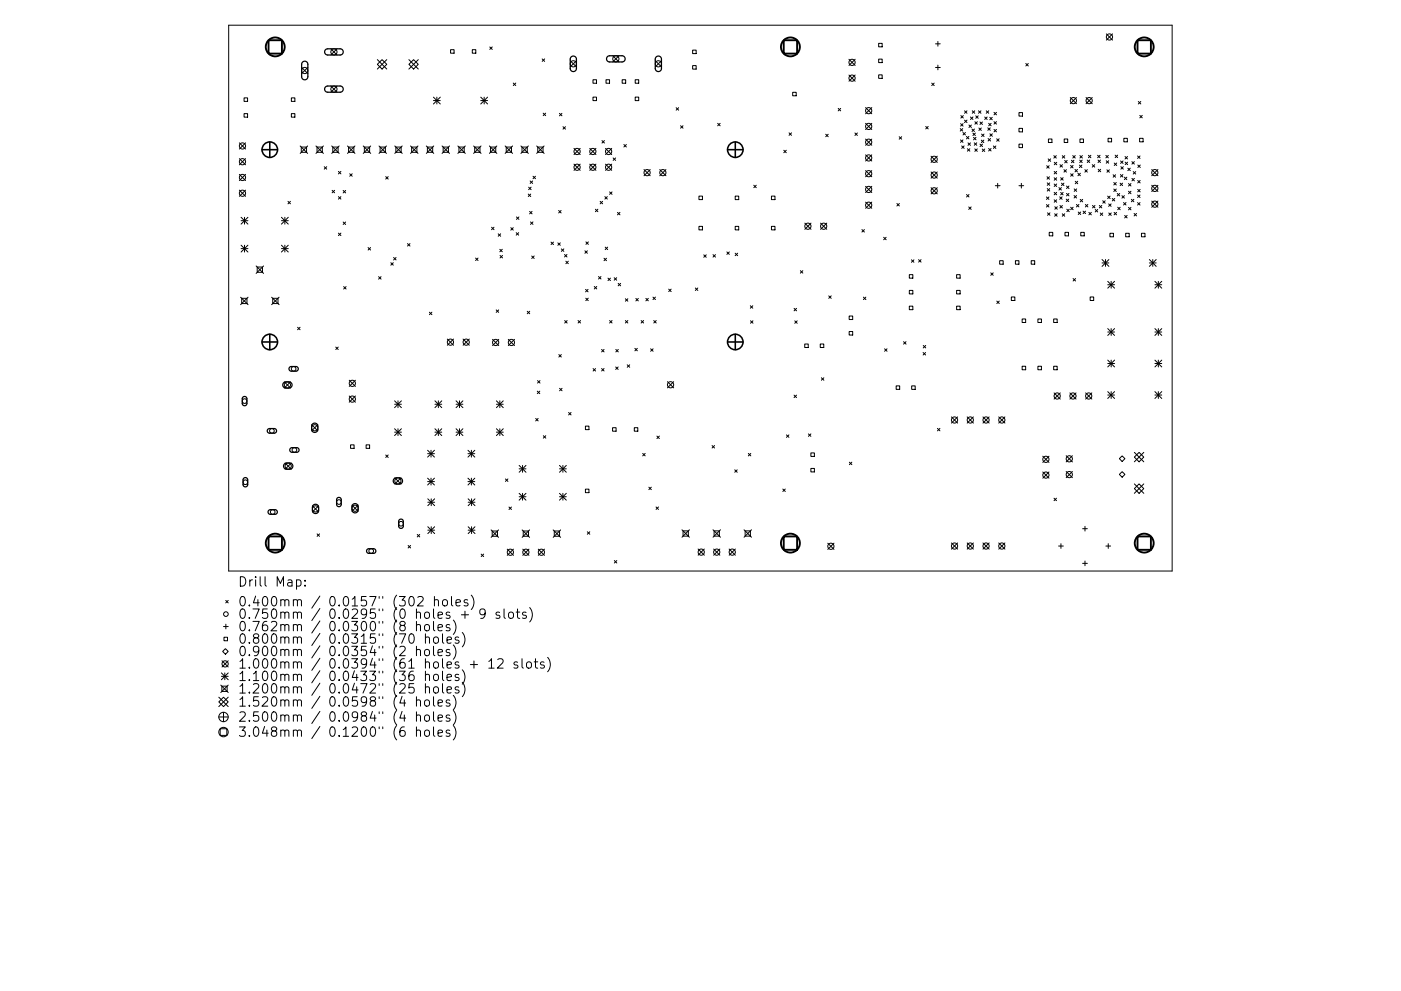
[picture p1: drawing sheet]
<svg xmlns="http://www.w3.org/2000/svg" width="297mm" height="210mm" viewBox="0 0 297 210" stroke-linecap="round" stroke-linejoin="round" font-family="sans-serif">
<defs><g id="words">
<g font-size="2.8">
<text x="50.4" y="125.1">Drill</text>
<text x="58.4" y="125.1">Map:</text>
<text x="50.4" y="129.3">0.400mm</text>
<text x="50.4" y="131.9">0.750mm</text>
<text x="69.8" y="129.3">0.0157&quot;</text>
<text x="69.8" y="131.9">0.0295&quot;</text>
<text x="83.6" y="129.3">(302</text>
<text x="83.6" y="131.9">(0</text>
<text x="88.5" y="131.9">holes</text>
<text x="92.3" y="129.3">holes)</text>
<text x="98.2" y="131.9">+</text>
<text x="102.4" y="131.9">9</text>
<text x="106.1" y="131.9">slots)</text>
<text x="50.4" y="134.5">0.762mm</text>
<text x="50.4" y="137.2">0.800mm</text>
<text x="69.8" y="134.5">0.0300&quot;</text>
<text x="69.8" y="137.2">0.0315&quot;</text>
<text x="83.6" y="134.5">(8</text>
<text x="83.6" y="137.2">(70</text>
<text x="88.5" y="134.5">holes)</text>
<text x="90.4" y="137.2">holes)</text>
<text x="50.4" y="139.8">0.900mm</text>
<text x="50.4" y="142.5">1.000mm</text>
<text x="69.8" y="139.8">0.0354&quot;</text>
<text x="69.8" y="142.5">0.0394&quot;</text>
<text x="83.6" y="139.8">(2</text>
<text x="83.6" y="142.5">(61</text>
<text x="88.5" y="139.8">holes)</text>
<text x="90.4" y="142.5">holes</text>
<text x="100.1" y="142.5">+</text>
<text x="109.9" y="142.5">slots)</text>
<text x="50.4" y="145.1">1.100mm</text>
<text x="50.4" y="147.8">1.200mm</text>
<text x="69.8" y="145.1">0.0433&quot;</text>
<text x="69.8" y="147.8">0.0472&quot;</text>
<text x="83.6" y="145.1">(36</text>
<text x="83.6" y="147.8">(25</text>
<text x="90.4" y="145.1">holes)</text>
<text x="90.4" y="147.8">holes)</text>
<text x="50.4" y="150.5">1.520mm</text>
<text x="50.4" y="153.7">2.500mm</text>
<text x="69.8" y="150.5">0.0598&quot;</text>
<text x="69.8" y="153.7">0.0984&quot;</text>
<text x="83.6" y="150.5">(4</text>
<text x="83.6" y="153.7">(4</text>
<text x="88.5" y="150.5">holes)</text>
<text x="88.5" y="153.7">holes)</text>
<text x="50.4" y="156.9">3.048mm</text>
<text x="69.8" y="156.9">0.1200&quot;</text>
<text x="83.6" y="156.9">(6</text>
<text x="88.5" y="156.9">holes)</text>
</g>
</g></defs>
<g fill="none" stroke="#000" stroke-width=".21">
<path d="M48.5 5.3h200v115.9h-200zM64 14.3l1.3 1.3M65.3 14.3l-1.3 1.3M70.1 10.4l1.4 1.3M70.1 18.3l1.4 1.3M71.5 10.4l-1.4 1.3M71.5 18.3l-1.4 1.3M80 12.7l2 2M81 12.7l1 1-1 1-1-1zM82 12.7l-2 2M86.7 12.7l2 2M87.7 12.7l1 1-1 1-1-1z"/>
<path d="M88.7 12.7l-2 2M95.5 10.5h.8v.8h-.8zM100.1 10.5h.8v.8h-.8zM103.8 10l.6 .5M104.4 10l-.6 .5M108.8 17.6l.6 .6M109.4 17.6l-.6 .6M114.9 12.5l.6 .5M115.5 12.5l-.6 .5M120.9 12.9l1.3 1.3M122.2 12.9l-1.3 1.3M125.7 16.9h.8v.8h-.8z"/>
<path d="M128.5 16.9h.7v.8h-.7zM129.9 11.8l1.3 1.3M131.2 11.8l-1.3 1.3M131.9 16.9h.8v.8h-.8zM134.7 16.9h.7v.8h-.7zM138.9 12.9l1.3 1.3M140.2 12.9l-1.3 1.3M146.9 10.6h.7v.8h-.7zM146.9 13.9h.7v.8h-.7zM168.1 19.6h.7v.7h-.7zM180 12.6l1.3 1.3M180 15.9l1.3 1.3"/>
<path d="M181.3 12.6l-1.3 1.3M181.3 15.9l-1.3 1.3M186.3 9.2h.7v.7h-.7zM186.3 12.5h.7v.8h-.7zM186.3 15.9h.7v.7h-.7zM197.5 17.6l.6 .6M198.1 17.6l-.6 .6M198.3 9.3h1.1M198.3 14.3h1.1M198.9 8.8v1M198.9 13.8v1M217.5 13.5l.5 .5"/>
<path d="M218 13.5l-.5 .5M234.6 7.2l1.3 1.3M235.9 7.2l-1.3 1.3M50.7 30.3l1.4 1.3M50.7 33.7l1.4 1.3M50.7 37l1.4 1.3M51.7 20.8h.8v.7h-.8zM51.7 24.1h.8v.8h-.8zM52.1 30.3l-1.4 1.3M52.1 33.7l-1.4 1.3M52.1 37l-1.4 1.3M61.8 20.8h.7v.7h-.7z"/>
<path d="M61.8 24.1h.7v.8h-.7zM63.6 31l1.6 1.5M63.9 31.2h1.1v1.1h-1.1zM65.2 31l-1.6 1.5M67 31l1.6 1.5M67.2 31.2h1.1v1.1h-1.1zM68.6 31l-1.6 1.5M68.7 35.4l.6 .5M69.3 35.4l-.6 .5M70.3 31l1.6 1.5M70.6 31.2h1.1v1.1h-1.1zM71.8 36.4l.5 .5"/>
<path d="M71.9 31l-1.6 1.5M72.3 36.4l-.5 .5M73.7 31l1.6 1.5M73.9 31.2h1.1v1.1h-1.1zM74.1 36.9l.6 .5M74.7 36.9l-.6 .5M75.3 31l-1.6 1.5M77 31l1.6 1.5M77.2 31.2h1.2v1.1h-1.2zM78.6 31l-1.6 1.5M80.4 31l1.5 1.5M80.6 31.2h1.1v1.1h-1.1z"/>
<path d="M81.8 37.5l.5 .5M81.9 31l-1.5 1.5M82.3 37.5l-.5 .5M83.7 31l1.6 1.5M83.9 31.2h1.1v1.1h-1.1zM85.3 31l-1.6 1.5M87 31l1.6 1.5M87.3 31.2h1.1v1.1h-1.1zM88.6 31l-1.6 1.5M90.4 31l1.6 1.5M90.6 31.2h1.1v1.1h-1.1zM91.9 20.6l1.4 1.5"/>
<path d="M91.9 21.3h1.4M92 31l-1.6 1.5M92.6 20.6v1.5M93.3 20.6l-1.4 1.5M93.7 31l1.6 1.5M94 31.2h1.1v1.1h-1.1zM95.3 31l-1.6 1.5M97.1 31l1.6 1.5M97.3 31.2h1.1v1.1h-1.1zM98.7 31l-1.6 1.5M100.4 31l1.6 1.5M100.6 31.2h1.2v1.1h-1.2z"/>
<path d="M101.9 21.3h1.5M101.9 20.6l1.5 1.5M102 31l-1.6 1.5M102.7 20.6v1.5M103.4 20.6l-1.5 1.5M103.8 31l1.5 1.5M104 31.2h1.1v1.1h-1.1zM105.3 31l-1.5 1.5M107.1 31l1.6 1.5M107.3 31.2h1.1v1.1h-1.1zM108.7 31l-1.6 1.5M110.4 31l1.6 1.5"/>
<path d="M110.7 31.2h1.1v1.1h-1.1zM112 31l-1.6 1.5M112.1 39.7l.5 .5M112.4 38.4l.5 .5M112.6 39.7l-.5 .5M112.9 38.4l-.5 .5M113 37.4l.5 .5M113.5 37.4l-.5 .5M113.8 31l1.6 1.5M114 31.2h1.1v1.1h-1.1zM115.2 24l.5 .5M115.4 31l-1.6 1.5"/>
<path d="M115.7 24l-.5 .5M118.6 24l.5 .6M119.1 24l-.5 .6M119.4 26.9l.5 .5M119.9 26.9l-.5 .5M121.7 31.5l1.3 1.3M121.7 34.8l1.3 1.3M123 31.5l-1.3 1.3M123 34.8l-1.3 1.3M125 31.5l1.4 1.3M125 34.8l1.4 1.3M125.7 20.6h.8v.7h-.8z"/>
<path d="M126.4 31.5l-1.4 1.3M126.4 34.8l-1.4 1.3M127.6 29.8l.6 .6M128.2 29.8l-.6 .6M128.4 34.8l1.3 1.3M128.4 31.5l1.3 1.3M129.7 31.5l-1.3 1.3M129.7 34.8l-1.3 1.3M130 33.5l.5 .5M130.5 33.5l-.5 .5M132.3 30.7l.5 .5M132.8 30.7l-.5 .5"/>
<path d="M134.7 20.6h.7v.7h-.7zM136.5 36l1.4 1.3M137.9 36l-1.4 1.3M139.9 36l1.3 1.3M141.2 36l-1.3 1.3M143.4 22.8l.5 .6M143.9 22.8l-.5 .6M144.3 26.7l.5 .5M144.8 26.7l-.5 .5M152.2 26.2l.5 .5M152.7 26.2l-.5 .5M159.8 39.3l.5 .5"/>
<path d="M160.3 39.3l-.5 .5M166.2 31.9l.5 .5M166.7 31.9l-.5 .5M167.3 28.2l.5 .5M167.8 28.2l-.5 .5M175.1 28.5l.5 .5M175.6 28.5l-.5 .5M177.7 23l.5 .5M178.2 23l-.5 .5M181.3 28.2l.5 .5M181.8 28.2l-.5 .5M183.5 22.8l1.3 1.3"/>
<path d="M183.5 26.2l1.3 1.3M183.5 29.5l1.3 1.3M183.5 32.9l1.3 1.3M183.5 36.2l1.3 1.3M183.5 39.5l1.3 1.4M184.8 22.8l-1.3 1.3M184.8 26.2l-1.3 1.3M184.8 29.5l-1.3 1.3M184.8 32.9l-1.3 1.3M184.8 36.2l-1.3 1.3M184.8 39.5l-1.3 1.4M190.6 29l.6 .5"/>
<path d="M191.2 29l-.6 .5M196.3 26.8l.5 .6M196.8 26.8l-.5 .6M197.4 33.1l1.3 1.4M197.4 36.5l1.3 1.3M197.4 39.8l1.3 1.3M198.7 36.5l-1.3 1.3M198.7 33.1l-1.3 1.4M198.7 39.8l-1.3 1.3M203.6 27.3l.5 .5M203.6 29.7l.6 .5M203.7 26.2l.5 .6"/>
<path d="M203.7 24.5l.5 .5M203.9 31l.5 .5M204.1 27.3l-.5 .5M204.2 28.1l.5 .5M204.2 29.7l-.6 .5M204.2 26.2l-.5 .6M204.2 24.5l-.5 .5M204.4 31l-.5 .5M204.5 23.5l.5 .5M204.5 25.5l.5 .5M204.7 28.1l-.5 .5M204.9 28.9l.5 .6"/>
<path d="M205 23.5l-.5 .5M205 25.5l-.5 .5M205.1 31.5l.5 .6M205.2 30.3l.6 .5M205.4 28.9l-.5 .6M205.4 26.5l.6 .5M205.6 31.5l-.5 .6M205.8 30.3l-.6 .5M205.8 24.8l.5 .6M206 26.5l-.6 .5M206.1 27.4l.5 .5M206.1 23.5l.6 .5"/>
<path d="M206.3 28.2l.5 .6M206.3 24.8l-.5 .6M206.4 29.1l.5 .6M206.6 30.3l.5 .5M206.6 27.4l-.5 .5M206.7 23.5l-.6 .5M206.7 31.6l.5 .5M206.7 25.8l.5 .6M206.8 28.2l-.5 .6M206.9 24.6l.5 .5M206.9 29.1l-.5 .6M207.1 30.3l-.5 .5"/>
<path d="M207.2 31.6l-.5 .5M207.2 25.8l-.5 .6M207.4 24.6l-.5 .5M207.5 23.5l.5 .5M207.5 27.2l.6 .5M207.8 25.9l.5 .5M207.8 30.6l.5 .5M208 23.5l-.5 .5M208.1 27.2l-.6 .5M208.1 29.7l.5 .6M208.1 28.4l.5 .6M208.3 31.6l.5 .5"/>
<path d="M208.3 25.9l-.5 .5M208.3 30.6l-.5 .5M208.6 29.7l-.5 .6M208.6 28.4l-.5 .6M208.8 24.8l.5 .6M208.8 31.6l-.5 .5M209.1 23.5l.5 .5M209.3 24.8l-.5 .6M209.4 27.1l.6 .6M209.5 29.4l.5 .5M209.6 31.5l.5 .5M209.6 26.2l.5 .5"/>
<path d="M209.6 23.5l-.5 .5M209.9 24.9l.5 .5M209.9 28.4l.5 .5M210 27.1l-.6 .6M210 29.4l-.5 .5M210.1 31.5l-.5 .5M210.1 26.2l-.5 .5M210.4 24.9l-.5 .5M210.4 28.4l-.5 .5M210.6 31l.5 .5M210.7 25.8l.6 .5M210.7 23.8l.6 .6"/>
<path d="M210.7 27.5l.6 .5M211 39.4h1M211.1 31l-.5 .5M211.3 25.8l-.6 .5M211.3 23.8l-.6 .6M211.3 27.5l-.6 .5M211.3 29.4l.5 .6M211.5 38.9v1M211.8 29.4l-.5 .6M216 39.4h1M216 23.9h.8v.7h-.8zM216 27.2h.8v.8h-.8z"/>
<path d="M216 30.6h.8v.7h-.8zM216.5 38.9v1M221.9 35.2l.5 .5M222 37.5l.5 .5M222 38.8l.6 .5M222.2 33.7l.6 .5M222.3 29.5h.7v.7h-.7zM222.4 35.2l-.5 .5M222.5 37.5l-.5 .5M222.6 38.8l-.6 .5M222.8 33.7l-.6 .5M223.4 33l.6 .5"/>
<path d="M223.5 39l.5 .6M223.5 36.4l.5 .5M223.5 37.7l.5 .5M223.5 34.4l.6 .6M224 33l-.6 .5M224 36.4l-.5 .5M224 37.7l-.5 .5M224 39l-.5 .6M224.1 34.4l-.6 .6M224.5 39.8l.5 .5M224.7 34.9l.6 .6M224.9 37.7l.5 .5"/>
<path d="M225 39.8l-.5 .5M225.1 38.9l.5 .5M225.2 33l.5 .5M225.3 34.9l-.6 .6M225.4 37.7l-.5 .5M225.6 38.9l-.5 .5M225.6 36l.5 .5M225.6 29.5h.8v.7h-.8zM225.7 34l.6 .6M225.7 33l-.5 .5M226.1 36l-.5 .5M226.1 39.5l.5 .5"/>
<path d="M226.3 34l-.6 .6M226.6 39.5l-.5 .5M226.9 20.7l1.3 1.3M227 35.1l.5 .5M227 36.9l.5 .5M227.2 34l.5 .5M227.4 33l.6 .5M227.5 35.1l-.5 .5M227.5 36.9l-.5 .5M227.7 34l-.5 .5M227.9 36l.5 .5M228 33l-.6 .5"/>
<path d="M228 38.5l.5 .5M228.2 20.7l-1.3 1.3M228.4 36l-.5 .5M228.5 38.5l-.5 .5M228.5 36.8l.6 .5M228.9 35l.5 .6M228.9 34l.5 .5M229 33l.5 .5M229 29.5h.7v.7h-.7zM229.1 36.8l-.6 .5M229.4 35l-.5 .6M229.4 34l-.5 .5"/>
<path d="M229.5 33l-.5 .5M230 36l.5 .5M230.3 20.7l1.3 1.3M230.5 34l.5 .5M230.5 36l-.5 .5M230.8 32.9l.5 .6M231 34l-.5 .5M231.3 32.9l-.5 .6M231.6 34.9l.5 .6M231.6 20.7l-1.3 1.3M232.1 34.9l-.5 .6M232.7 32.9l.5 .6"/>
<path d="M232.8 34l.5 .5M232.8 35.9l.6 .5M233.2 32.9l-.5 .6M233.3 34l-.5 .5M233.4 35.9l-.6 .5M234.5 33l.5 .5M234.5 34.1l.6 .5M234.7 36l.5 .5M234.9 29.3h.8v.8h-.8zM235 33l-.5 .5M235.1 34.1l-.6 .5M235.2 36l-.5 .5"/>
<path d="M236 37.1l.5 .5M236.1 38.7l.6 .5M236.2 34.6l.6 .5M236.4 32.9l.6 .5M236.5 37.1l-.5 .5M236.7 38.7l-.6 .5M236.8 34.6l-.6 .5M237 32.9l-.6 .5M237.5 38.9l.5 .5M237.5 37l.6 .6M237.6 34.1l.5 .6M237.6 35.4l.6 .5"/>
<path d="M238 38.9l-.5 .5M238.1 37l-.6 .6M238.1 34.1l-.5 .6M238.2 35.4l-.6 .5M238.3 29.3h.7v.8h-.7zM238.4 37.6l.5 .5M238.5 33.2l.6 .5M238.6 34.4l.5 .5M238.9 37.6l-.5 .5M239.1 33.2l-.6 .5M239.1 34.4l-.5 .5M239.1 35.7l.5 .5"/>
<path d="M239.3 38.9l.5 .6M239.6 35.7l-.5 .5M239.8 38.9l-.5 .6M240 34.3l.5 .5M240 37.9l.5 .5M240.3 36.4l.5 .5M240.5 34.3l-.5 .5M240.5 37.9l-.5 .5M240.8 36.4l-.5 .5M241.2 33.1l.5 .5M241.2 38.3l.5 .5M241.2 35l.6 .5"/>
<path d="M241.3 21.5l.6 .6M241.6 29.3h.8v.8h-.8zM241.7 24.5l.5 .5M241.7 33.1l-.5 .5M241.7 38.3l-.5 .5M241.8 35l-.6 .5M241.9 21.5l-.6 .6M242.2 24.5l-.5 .5M244.2 36l1.3 1.3M244.2 39.3l1.3 1.3M245.5 36l-1.3 1.3M245.5 39.3l-1.3 1.3"/>
<path d="M50.7 40.3l1.4 1.4M51.1 46.1l1.5 1.5M51.1 46.8h1.5M51.1 52l1.5 1.5M51.1 52.7h1.5M51.8 46.1v1.5M51.8 52v1.5M52.1 40.3l-1.4 1.4M52.6 46.1l-1.5 1.5M52.6 52l-1.5 1.5M54.3 56.4l1.6 1.6M54.5 56.7h1.2v1.1h-1.2z"/>
<path d="M55.9 56.4l-1.6 1.6M59.7 46.8h1.4M59.7 52.7h1.4M59.7 46.1l1.4 1.5M59.7 52l1.4 1.5M60.4 46.1v1.5M60.4 52v1.5M61.1 42.7l.5 .5M61.1 46.1l-1.4 1.5M61.1 52l-1.4 1.5M61.6 42.7l-.5 .5M70.4 40.4l.5 .5"/>
<path d="M70.9 40.4l-.5 .5M71.8 41.7l.5 .5M71.8 49.5l.5 .5M72.3 41.7l-.5 .5M72.3 49.5l-.5 .5M72.8 40.4l.5 .5M72.8 47.1l.5 .5M73.3 40.4l-.5 .5M73.3 47.1l-.5 .5M78 52.5l.6 .6M78.6 52.5l-.6 .6M80.3 58.7l.5 .5"/>
<path d="M80.8 58.7l-.5 .5M82.9 55.7l.5 .6M83.4 55.7l-.5 .6M83.5 54.6l.5 .6M84 54.6l-.5 .6M86.4 51.7l.5 .5M86.9 51.7l-.5 .5M100.8 54.8l.6 .5M101.4 54.8l-.6 .5M104.2 48.2l.5 .5M104.7 48.2l-.5 .5M105.6 49.6l.6 .5"/>
<path d="M106 52.9l.5 .5M106 54.2l.5 .5M106.2 49.6l-.6 .5M106.5 52.9l-.5 .5M106.5 54.2l-.5 .5M108.3 48.3l.5 .5M108.8 48.3l-.5 .5M109.4 49.4l.6 .5M109.5 46l.5 .6M110 49.4l-.6 .5M110 46l-.5 .6M112 41.2l.5 .5"/>
<path d="M112.3 44.9l.5 .5M112.5 47.1l.5 .5M112.5 41.2l-.5 .5M112.7 54.3l.6 .5M112.8 44.9l-.5 .5M113 47.1l-.5 .5M113.3 54.3l-.6 .5M116.8 51.4l.6 .5M117.4 51.4l-.6 .5M118.3 51.5l.5 .5M118.4 44.7l.6 .5M118.8 51.5l-.5 .5"/>
<path d="M119 44.7l-.6 .5M119 52.8l.5 .5M119.5 52.8l-.5 .5M119.7 54l.5 .5M120 55.4l.5 .5M120.2 54l-.5 .5M120.5 55.4l-.5 .5M124 53.2l.5 .5M124.2 51.3l.6 .5M124.5 53.2l-.5 .5M124.8 51.3l-.6 .5M126.2 44.4l.6 .5"/>
<path d="M126.8 44.4l-.6 .5M126.9 58.7l.5 .5M127.2 42.7l.6 .5M127.4 58.7l-.5 .5M127.8 42.7l-.6 .5M128.1 54.8l.5 .5M128.2 41.7l.6 .5M128.3 52.4l.5 .6M128.6 54.8l-.5 .5M128.8 41.7l-.6 .5M128.8 52.4l-.5 .6M128.9 59l.5 .5"/>
<path d="M129.2 40.7l.6 .5M129.4 59l-.5 .5M129.8 40.7l-.6 .5M130.2 58.9l.5 .5M130.7 58.9l-.5 .5M130.9 45.1l.5 .5M131.4 45.1l-.5 .5M148.2 41.6h.7v.8h-.7zM148.2 48h.7v.8h-.7zM149.2 54.1l.5 .5M149.7 54.1l-.5 .5M151.2 54l.5 .6"/>
<path d="M151.7 54l-.5 .6M154.1 53.4l.5 .6M154.6 53.4l-.5 .6M155.9 53.7l.5 .5M155.9 41.6h.7v.8h-.7zM155.9 48h.7v.8h-.7zM156.4 53.7l-.5 .5M163.6 41.6h.7v.8h-.7zM163.6 48h.7v.8h-.7zM169.7 57.4l.5 .6M170.2 57.4l-.5 .6M170.6 47.3l1.3 1.4"/>
<path d="M171.9 47.3l-1.3 1.4M174 47.3l1.3 1.4M175.3 47.3l-1.3 1.4M182.7 48.7l.6 .5M183.3 48.7l-.6 .5M183.5 42.9l1.3 1.3M184.8 42.9l-1.3 1.3M187.4 50.3l.5 .6M187.9 50.3l-.5 .6M190.2 43.2l.5 .5M190.7 43.2l-.5 .5M192.8 58.3h.7v.7h-.7z"/>
<path d="M193.2 55.1l.6 .6M193.8 55.1l-.6 .6M194.8 55.1l.5 .5M195.3 55.1l-.5 .5M202.8 58.3h.8v.7h-.8zM204.9 41.3l.6 .5M205.4 43.9l.5 .5M205.5 41.3l-.6 .5M205.9 43.9l-.5 .5M210.1 57.9l.5 .5M210.6 57.9l-.5 .5M211.9 55.3h.8v.8h-.8z"/>
<path d="M215.3 55.3h.7v.8h-.7zM218.6 55.3h.8v.8h-.8zM221.9 41.8l.5 .5M221.9 43.4l.5 .5M222 40l.6 .5M222.1 45.2l.5 .5M222.4 41.8l-.5 .5M222.4 43.4l-.5 .5M222.5 49.3h.7v.7h-.7zM222.6 40l-.6 .5M222.6 45.2l-.5 .5M223.5 40.8l.5 .5"/>
<path d="M223.5 42.4l.5 .5M223.6 45.4l.5 .5M223.6 43.9l.6 .5M224 40.8l-.5 .5M224 42.4l-.5 .5M224.1 45.4l-.5 .5M224.2 43.9l-.6 .5M224.7 41.8l.5 .5M224.7 43.6l.6 .5M224.9 40.8l.5 .6M225.2 41.8l-.5 .5M225.2 45.4l.5 .5"/>
<path d="M225.3 43.6l-.6 .5M225.4 40.8l-.5 .6M225.7 45.4l-.5 .5M225.8 49.3h.7v.7h-.7zM226.1 42.2l.5 .6M226.1 41l.5 .6M226.2 44.4l.5 .5M226.6 42.2l-.5 .6M226.6 41l-.5 .6M226.7 44.4l-.5 .5M227 44l.5 .5M227.5 59.1l.5 .5"/>
<path d="M227.5 44l-.5 .5M227.7 41.5l.5 .5M227.7 40.1l.6 .5M228 59.1l-.5 .5M228.2 43.4l.6 .5M228.2 41.5l-.5 .5M228.3 40.1l-.6 .5M228.6 45l.5 .5M228.8 43.4l-.6 .5M229 42.3l.6 .5M229.1 45l-.5 .5M229.1 49.3h.8v.7h-.8z"/>
<path d="M229.6 42.3l-.6 .5M229.6 44.8l.6 .5M230.1 43.4l.5 .5M230.2 44.8l-.6 .5M230.6 43.4l-.5 .5M230.9 45.1l.5 .5M231.4 45.1l-.5 .5M231.6 43.6l.6 .5M232.2 43.6l-.6 .5M232.2 44.4l.5 .6M232.7 44.4l-.5 .6M233.1 43.6l.5 .5"/>
<path d="M233.3 45.2l.5 .5M233.6 43.6l-.5 .5M233.7 55.1l1.4 1.4M233.7 55.8h1.4M233.8 45.2l-.5 .5M233.8 42.6l.5 .5M234.3 42.6l-.5 .5M234.4 55.1v1.4M234.8 41.6l.6 .5M234.9 59.7l1.4 1.4M235.1 43.3l.5 .5M235.1 45.2l.5 .5"/>
<path d="M235.1 55.1l-1.4 1.4M235.3 49.5h.8v.7h-.8zM235.4 41.6l-.6 .5M235.6 43.3l-.5 .5M235.6 59.7v1.4M235.6 45.2l-.5 .5M235.8 42.1l.5 .5M236.1 40.1l.6 .5M236.2 45.1l.5 .5M236.3 59.7l-1.4 1.4M236.3 42.1l-.5 .5M236.7 40.1l-.6 .5"/>
<path d="M236.7 45.1l-.5 .5M236.9 41l.5 .6M237 44l.5 .5M237.4 41l-.5 .6M237.5 44l-.5 .5M237.9 41.5l.5 .5M238.2 43l.5 .5M238.4 41.5l-.5 .5M238.4 45.7l.6 .5M238.7 49.5h.7v.7h-.7zM238.7 43l-.5 .5M239 45.7l-.6 .5"/>
<path d="M239.3 40.6l.5 .5M239.3 44l.5 .5M239.8 40.6l-.5 .5M239.8 44l-.5 .5M239.9 42.3l.5 .5M240.4 42.3l-.5 .5M240.4 45.3l.6 .5M241 45.3l-.6 .5M241.2 41.4l.5 .5M241.2 43l.5 .5M241.2 40.2l.5 .5M241.7 43l-.5 .5"/>
<path d="M241.7 41.4l-.5 .5M241.7 40.2l-.5 .5M242 49.5h.8v.7h-.8zM243.7 55.8h1.4M243.7 55.1l1.4 1.4M244.2 42.7l1.3 1.3M244.4 55.1v1.4M244.9 59.7l1.4 1.4M245.1 55.1l-1.4 1.4M245.5 42.7l-1.3 1.3M245.6 59.7v1.4M246.3 59.7l-1.4 1.4"/>
<path d="M51 63.1l1.6 1.5M51.2 63.3h1.2v1.1h-1.2zM52.6 63.1l-1.6 1.5M57.6 63.1l1.6 1.5M57.8 63.3h1.1v1.1h-1.1zM59.2 63.1l-1.6 1.5M63.1 69.4l.5 .6M63.6 69.4l-.5 .6M71.2 73.6l.5 .6M71.7 73.6l-.5 .6M72.9 60.8l.5 .5M73.4 60.8l-.5 .5"/>
<path d="M91 66.2l.6 .6M91.6 66.2l-.6 .6M94.8 71.9l1.4 1.4M96.2 71.9l-1.4 1.4M98.2 71.9l1.3 1.4M99.5 71.9l-1.3 1.4M104.4 72l1.3 1.3M105.2 65.8l.5 .5M105.7 65.8l-.5 .5M105.7 72l-1.3 1.3M107.8 72l1.3 1.3M109.1 72l-1.3 1.3"/>
<path d="M111.8 66l.5 .6M112.3 66l-.5 .6M118.5 75.2l.5 .6M119 75.2l-.5 .6M119.7 68l.5 .5M120.2 68l-.5 .5M122.6 68l.5 .5M123.1 68l-.5 .5M124.2 61.4l.5 .5M124.2 63.3l.5 .5M124.7 61.4l-.5 .5M124.7 63.3l-.5 .5"/>
<path d="M125.7 78.2l.6 .5M126 60.8l.5 .5M126.3 78.2l-.6 .5M126.5 60.8l-.5 .5M127.6 74.1l.5 .6M127.6 78.2l.5 .5M128.1 74.1l-.5 .6M128.1 78.2l-.5 .5M129.2 68l.6 .5M129.8 68l-.6 .5M130.5 77.9l.6 .5M130.6 74.1l.5 .6"/>
<path d="M131.1 77.9l-.6 .5M131.1 60.1l.5 .5M131.1 74.1l-.5 .6M131.6 60.1l-.5 .5M132.6 68l.5 .5M132.6 63.4l.5 .5M133 77.4l.5 .5M133.1 68l-.5 .5M133.1 63.4l-.5 .5M133.5 77.4l-.5 .5M134.6 73.9l.5 .5M134.8 63.3l.5 .5"/>
<path d="M135.1 73.9l-.5 .5M135.3 63.3l-.5 .5M135.9 68l.6 .5M136.5 68l-.6 .5M136.9 63.3l.6 .5M137.5 63.3l-.6 .5M137.9 74l.6 .5M138.4 63l.6 .6M138.5 74l-.6 .5M138.6 68l.5 .5M139 63l-.6 .6M139.1 68l-.5 .5"/>
<path d="M141.8 61.3l.5 .6M142.3 61.3l-.5 .6M147.4 61.1l.6 .5M148 61.1l-.6 .5M159.1 64.9l.5 .5M159.1 68.1l.5 .5M159.6 64.9l-.5 .5M159.6 68.1l-.5 .5M168.4 65.4l.5 .5M168.5 68.1l.5 .5M168.9 65.4l-.5 .5M169 68.1l-.5 .5"/>
<path d="M170.6 73h.8v.7h-.8zM173.9 73h.8v.7h-.8zM175.7 62.8l.5 .5M176.2 62.8l-.5 .5M180 67.1h.8v.7h-.8zM180 70.3h.8v.8h-.8zM183.1 63l.5 .6M183.6 63l-.5 .6M187.5 74l.6 .5M188.1 74l-.6 .5M191.6 72.5l.5 .5M192.1 72.5l-.5 .5"/>
<path d="M192.8 61.6h.7v.8h-.7zM192.8 65h.7v.7h-.7zM195.7 74.8l.5 .5M195.7 73.3l.6 .5M196.2 74.8l-.5 .5M196.3 73.3l-.6 .5M202.8 61.6h.8v.8h-.8zM202.8 65h.8v.7h-.8zM211.3 63.9l.6 .5M211.9 63.9l-.6 .5M214.4 63h.8v.8h-.8zM216.7 67.7h.8v.7h-.8z"/>
<path d="M216.7 77.7h.8v.8h-.8zM220.1 67.7h.7v.7h-.7zM220.1 77.7h.7v.8h-.7zM223.4 67.7h.7v.7h-.7zM223.4 77.7h.7v.8h-.7zM231.1 63h.8v.8h-.8zM234.9 60.4h1.4M234.9 69.7l1.4 1.5M234.9 70.4h1.4M234.9 76.4l1.4 1.5M234.9 77.1h1.4M235.6 69.7v1.5"/>
<path d="M235.6 76.4v1.5M236.3 69.7l-1.4 1.5M236.3 76.4l-1.4 1.5M244.9 69.7l1.4 1.5M244.9 76.4l1.4 1.5M244.9 60.4h1.4M244.9 70.4h1.4M244.9 77.1h1.4M245.6 69.7v1.5M245.6 76.4v1.5M246.3 69.7l-1.4 1.5M246.3 76.4l-1.4 1.5"/>
<path d="M60.3 81l1.3 1.3M60.4 98.2l1.4 1.3M61.6 81l-1.3 1.3M61.8 98.2l-1.4 1.3M66.1 90.1l1.3 1.3M67.4 90.1l-1.3 1.3M74 80.7l1.4 1.3M74 84l1.4 1.3M74.3 94.4h.8v.7h-.8zM75.4 84l-1.4 1.3M75.4 80.7l-1.4 1.3M77.6 94.4h.8v.7h-.8z"/>
<path d="M81.8 96.5l.5 .6M82.3 96.5l-.5 .6M83.7 85l1.4 1.5M83.7 85.8h1.4M83.7 91l1.4 1.4M83.7 91.7h1.4M84.4 85v1.5M84.4 91v1.4M85.1 91l-1.4 1.4M85.1 85l-1.4 1.5M90.7 95.5l1.4 1.5M90.7 96.3h1.4"/>
<path d="M91.4 95.5v1.5M92.1 95.5l-1.4 1.5M92.2 85.8h1.5M92.2 91.7h1.5M92.2 85l1.5 1.5M92.2 91l1.5 1.4M92.9 85v1.5M92.9 91v1.4M93.7 85l-1.5 1.5M93.7 91l-1.5 1.4M96.7 85l1.4 1.5M96.7 85.8h1.4"/>
<path d="M96.7 91.7h1.4M96.7 91l1.4 1.4M97.4 85v1.5M97.4 91v1.4M98.1 85l-1.4 1.5M98.1 91l-1.4 1.4M99.2 96.3h1.5M99.2 95.5l1.5 1.5M99.9 95.5v1.5M100.7 95.5l-1.5 1.5M105.2 85.8h1.5M105.2 91.7h1.5"/>
<path d="M105.2 85l1.5 1.5M105.2 91l1.5 1.4M106 85v1.5M106 91v1.4M106.7 85l-1.5 1.5M106.7 91l-1.5 1.4M110.1 98.7l1.4 1.5M110.1 99.5h1.4M110.8 98.7v1.5M111.5 98.7l-1.4 1.5M113.6 88.8l.5 .5M113.9 83l.5 .5"/>
<path d="M114 80.8l.5 .5M114.1 88.8l-.5 .5M114.4 83l-.5 .5M114.5 80.8l-.5 .5M115.2 92.4l.5 .6M115.7 92.4l-.5 .6M118.6 99.5h1.5M118.6 98.7l1.5 1.5M118.6 82.4l.6 .5M119.2 82.4l-.6 .5M119.3 98.7v1.5M120.1 98.7l-1.5 1.5"/>
<path d="M120.6 87.5l.5 .5M121.1 87.5l-.5 .5M124.1 90.4h.8v.8h-.8zM129.9 90.7h.7v.8h-.7zM134.5 90.7h.7v.8h-.7zM136.3 96.2l.5 .5M136.8 96.2l-.5 .5M139.3 92.5l.5 .5M139.8 92.5l-.5 .5M141.5 81l1.3 1.3M142.8 81l-1.3 1.3M151 94.5l.5 .6"/>
<path d="M151.5 94.5l-.5 .6M155.8 99.7l.5 .5M156.3 99.7l-.5 .5M158.7 96.2l.5 .5M159.2 96.2l-.5 .5M166.7 92.3l.6 .5M167.3 92.3l-.6 .5M168.4 83.8l.5 .6M168.9 83.8l-.5 .6M171.4 92.1l.5 .5M171.9 96.1h.8v.7h-.8zM171.9 99.4h.8v.7h-.8z"/>
<path d="M171.9 92.1l-.5 .5M174.1 80.1l.6 .6M174.7 80.1l-.6 .6M180.1 98.1l.5 .5M180.6 98.1l-.5 .5M190 81.9h.7v.7h-.7zM193.3 81.9h.7v.7h-.7zM198.8 90.9l.5 .5M199.3 90.9l-.5 .5M201.7 88.5l1.3 1.3M203 88.5l-1.3 1.3M205.1 88.5l1.3 1.3"/>
<path d="M206.4 88.5l-1.3 1.3M208.4 88.5l1.3 1.3M209.7 88.5l-1.3 1.3M211.7 88.5l1.4 1.3M213.1 88.5l-1.4 1.3M221.1 96.8l1.3 1.3M222.4 96.8l-1.3 1.3M223.5 83.4l1.3 1.3M224.8 83.4l-1.3 1.3M226.1 96.7l1.3 1.3M226.8 83.4l1.3 1.3M227.4 96.7l-1.3 1.3"/>
<path d="M228.1 83.4l-1.3 1.3M230.2 83.4l1.3 1.3M231.5 83.4l-1.3 1.3M234.9 83.1l1.4 1.4M234.9 83.8h1.4M235.6 83.1v1.4M236.3 83.1l-1.4 1.4M237.3 97.3l.6-.6 .6 .6-.6 .6zM240.5 97l1-1 1 1-1 1zM240.5 96l2 2M242.5 96l-2 2M244.9 83.1l1.4 1.4"/>
<path d="M244.9 83.8h1.4M245.6 83.1v1.4M246.3 83.1l-1.4 1.4M66.2 107.3l1.4 1.3M67.2 113.3l.6 .5M67.6 107.3l-1.4 1.3M67.8 113.3l-.6 .5M74.6 107.2l1.3 1.3M75.9 107.2l-1.3 1.3M83.7 101.4l1.3 1.3M85 101.4l-1.3 1.3M86.5 115.7l.6 .6"/>
<path d="M87.1 115.7l-.6 .6M88.5 113.4l.5 .5M89 113.4l-.5 .5M90.7 101.5l1.4 1.4M90.7 102.2h1.4M90.7 105.8l1.5 1.5M90.7 106.6h1.5M90.7 111.8l1.5 1.4M90.7 112.5h1.5M91.4 101.5v1.4M91.4 105.8v1.5M91.4 111.8v1.4"/>
<path d="M92.1 101.5l-1.4 1.4M92.2 105.8l-1.5 1.5M92.2 111.8l-1.5 1.4M99.2 102.2h1.5M99.2 101.5l1.5 1.4M99.3 106.6h1.4M99.3 112.5h1.4M99.3 105.8l1.4 1.5M99.3 111.8l1.4 1.4M99.9 101.5v1.4M100 105.8v1.5M100 111.8v1.4"/>
<path d="M100.7 101.5l-1.5 1.4M100.7 105.8l-1.4 1.5M100.7 111.8l-1.4 1.4M102 117.6l.5 .5M102.5 117.6l-.5 .5M104.1 112.4l1.6 1.6M104.4 112.7h1.1v1.1h-1.1zM105.7 112.4l-1.6 1.6M107.2 101.6l.5 .5M107.5 116.5l1.4 1.3M107.7 101.6l-.5 .5M107.9 107.6l.5 .5"/>
<path d="M108.4 107.6l-.5 .5M108.9 116.5l-1.4 1.3M110.1 104.7l1.4 1.4M110.1 105.4h1.4M110.7 112.4l1.6 1.6M110.8 104.7v1.4M110.8 116.5l1.4 1.3M110.9 112.7h1.2v1.1h-1.2zM111.5 104.7l-1.4 1.4M112.2 116.5l-1.4 1.3M112.3 112.4l-1.6 1.6M114.1 116.5l1.3 1.3"/>
<path d="M115.4 116.5l-1.3 1.3M117.3 112.4l1.6 1.6M117.5 112.7h1.1v1.1h-1.1zM118.6 104.7l1.5 1.4M118.6 105.4h1.5M118.9 112.4l-1.6 1.6M119.3 104.7v1.4M120.1 104.7l-1.5 1.4M124.1 103.8h.8v.7h-.8zM124.5 112.8l.6 .6M125.1 112.8l-.6 .6M130.2 118.9l.6 .6"/>
<path d="M130.8 118.9l-.6 .6M137.6 103.4l.5 .5M138.1 103.4l-.5 .5M139.1 107.6l.5 .5M139.6 107.6l-.5 .5M144.6 112.4l1.6 1.6M144.8 112.6h1.1v1.2h-1.1zM146.2 112.4l-1.6 1.6M148 116.5l1.3 1.3M149.3 116.5l-1.3 1.3M151.2 112.4l1.6 1.6M151.3 116.5l1.3 1.3"/>
<path d="M151.4 112.6h1.1v1.2h-1.1zM152.6 116.5l-1.3 1.3M152.8 112.4l-1.6 1.6M154.6 116.5l1.3 1.3M155.9 116.5l-1.3 1.3M157.8 112.4l1.5 1.6M158 112.6h1.1v1.2h-1.1zM159.3 112.4l-1.5 1.6M166 103.8l.5 .5M166.5 103.8l-.5 .5M175.5 115.2l1.3 1.4M176.8 115.2l-1.3 1.4"/>
<path d="M201.7 115.2l1.3 1.3M203 115.2l-1.3 1.3M205.1 115.2l1.3 1.3M206.4 115.2l-1.3 1.3M208.4 115.2l1.3 1.3M209.7 115.2l-1.3 1.3M211.7 115.2l1.4 1.3M213.1 115.2l-1.4 1.3M221.1 100.1l1.3 1.4M222.4 100.1l-1.3 1.4M223.5 105.7l.5 .5M224 105.7l-.5 .5"/>
<path d="M224.4 115.9h1M224.9 115.3v1.1M226.1 100l1.3 1.3M227.4 100l-1.3 1.3M229.5 112.2h1M229.5 119.5h1M230 111.7v1M230 119v1M234.5 115.9h1M235 115.3v1.1M237.3 100.7l.6-.6 .6 .6-.6 .5zM240.5 103.7l1-1 1 1-1 1z"/>
<path d="M240.5 102.7l2 2M242.5 102.7l-2 2M47.2 138.2l.6-.6 .6 .6-.6 .6zM47.4 132.9h1M47.5 135.2h.7v.7h-.7zM47.9 127.4l.5 .5M47.9 132.4v1M48.4 127.4l-.5 .5M56.2 122.4v1.7l.3 .3M62.2 127.4l.3-.2 .5 .1 .1 1.3M62.2 130.1a.5 .5 0 0 1 .9 0v1.1M62.2 132.7a.5 .5 0 0 1 .9 .1v1"/>
<path d="M62.2 135.3a.5 .5 0 0 1 .9 .1v1.1M62.2 138a.5 .5 0 0 1 .9 .1v1M63.1 127.5l.2-.3 .5 .1 .1 1.3M63.1 130.1l.2-.2 .5 .1 .1 1.2M63.1 132.8l.2-.3 .5 .1 .1 1.2M63.1 135.4l.2-.3 .5 .1 .1 1.3M63.1 138.1l.2-.3 .5 .1 .1 1.2M67.8 126.5l-1.7 2.5M67.8 129.1l-1.7 2.6M67.8 131.7l-1.7 2.6M67.8 134.4l-1.7 2.6M67.8 137l-1.7 2.6"/>
<path d="M67.8 139.7l-1.7 2.5M80.4 126.6v.3M80.4 129.2v.4M80.4 131.8v.4M80.4 134.5v.4M80.4 137.1v.4M80.4 139.8v.3M81.2 126.6v.3M81.2 129.2v.4M81.2 131.8v.4M81.2 134.5v.4M81.2 137.1v.4"/>
<path d="M81.2 139.8v.3M105.5 139.9l.3-.1 .7 .1a.54 .54 0 0 1 .1 .7l-1.2 1.2h1.3M105.9 130l-.5-.1-.2 .2v.3l.7 .2v.5h-.7M46.4 148.9l1-1 1 1-1 1zM46.4 147.9l2 2M46.4 152.1h2M46.7 154.6h1.4v1.4h-1.4zM46.8 145.4l1.6 1.5M46.9 142.8l1.5 1.4M46.9 143.5h1.5M47 145.6h1.2v1.1h-1.2zM47.1 140.2l1.3 1.3"/>
<path d="M47.4 151.1v2M47.7 142.8v1.4M48.4 140.2l-1.3 1.3M48.4 142.8l-1.5 1.4M48.4 145.4l-1.6 1.5M48.4 147.9l-2 2M62.2 140.6a.5 .5 0 0 1 .9 .1v1.1M62.2 143.3a.5 .5 0 0 1 .9 0v1.1M62.2 145.9a.5 .5 0 0 1 .9 .1v1M62.2 148.7a.5 .5 0 0 1 .9 .1v1M62.2 151.9a.5 .5 0 0 1 .9 .1v1M62.2 155.1a.5 .5 0 0 1 .9 .1v1"/>
<path d="M63.1 140.7l.2-.3 .5 .1 .1 1.3M63.1 143.3l.2-.2 .5 .1 .1 1.2M63.1 146l.2-.3 .5 .1 .1 1.2M63.1 148.8l.2-.3 .5 .1 .1 1.2M63.1 152l.2-.3 .5 .1 .1 1.2M63.1 155.2l.2-.3 .5 .1 .1 1.2M67.8 142.3l-1.7 2.6M67.8 144.9l-1.7 2.6M67.8 147.7l-1.7 2.6M67.8 150.9l-1.7 2.6M67.8 154.1l-1.7 2.6M80.4 142.4v.4"/>
<path d="M80.4 145v.4M80.4 147.8v.4M80.4 151v.4M80.4 154.2v.4M81.2 142.4v.4M81.2 145v.4M81.2 147.8v.4M81.2 151v.4M81.2 154.2v.4M103.6 140.3l.6-.5v2M103.6 141.8h1.2M109.7 140.5l-.5-.1-.2 .3 .1 .3 .6 .2v.5h-.7"/>
<circle cx="64.6" cy="15" r=".66"/>
<circle cx="70.8" cy="11" r=".66"/>
<circle cx="70.8" cy="18.9" r=".66"/>
<circle cx="121.6" cy="13.5" r=".66"/>
<circle cx="130.6" cy="12.5" r=".66"/>
<circle cx="139.6" cy="13.5" r=".66"/>
<circle cx="180.7" cy="16.6" r=".66"/>
<circle cx="180.7" cy="13.2" r=".66"/>
<circle cx="235.2" cy="7.8" r=".66"/>
<circle cx="51.4" cy="37.7" r=".66"/>
<circle cx="51.4" cy="34.3" r=".66"/>
<circle cx="51.4" cy="31" r=".66"/>
<circle cx="122.4" cy="32.1" r=".66"/>
<circle cx="122.4" cy="35.5" r=".66"/>
<circle cx="125.7" cy="35.5" r=".66"/>
<circle cx="125.7" cy="32.1" r=".66"/>
<circle cx="129" cy="35.5" r=".66"/>
<circle cx="129" cy="32.1" r=".66"/>
<circle cx="137.2" cy="36.6" r=".66"/>
<circle cx="140.5" cy="36.6" r=".66"/>
<circle cx="184.2" cy="36.9" r=".66"/>
<circle cx="184.2" cy="33.5" r=".66"/>
<circle cx="184.2" cy="26.8" r=".66"/>
<circle cx="184.2" cy="30.2" r=".66"/>
<circle cx="184.2" cy="23.5" r=".66"/>
<circle cx="198.1" cy="37.1" r=".66"/>
<circle cx="198.1" cy="33.8" r=".66"/>
<circle cx="227.6" cy="21.3" r=".66"/>
<circle cx="230.9" cy="21.3" r=".66"/>
<circle cx="244.8" cy="40" r=".66"/>
<circle cx="244.8" cy="36.6" r=".66"/>
<circle cx="51.4" cy="41" r=".66"/>
<circle cx="171.3" cy="48" r=".66"/>
<circle cx="174.6" cy="48" r=".66"/>
<circle cx="184.2" cy="40.2" r=".66"/>
<circle cx="184.2" cy="43.5" r=".66"/>
<circle cx="198.1" cy="40.5" r=".66"/>
<circle cx="244.8" cy="43.3" r=".66"/>
<circle cx="62.3" cy="78.3" r=".49"/>
<circle cx="95.5" cy="72.6" r=".66"/>
<circle cx="98.8" cy="72.6" r=".66"/>
<circle cx="105.1" cy="72.7" r=".66"/>
<circle cx="108.4" cy="72.7" r=".66"/>
<circle cx="51.9" cy="85.1" r=".49"/>
<circle cx="57.6" cy="91.4" r=".49"/>
<circle cx="60.9" cy="81.7" r=".66"/>
<circle cx="61.1" cy="98.9" r=".66"/>
<circle cx="62.4" cy="95.5" r=".49"/>
<circle cx="66.7" cy="90.8" r=".66"/>
<circle cx="74.7" cy="81.3" r=".66"/>
<circle cx="74.7" cy="84.7" r=".66"/>
<circle cx="142.2" cy="81.6" r=".66"/>
<circle cx="202.4" cy="89.1" r=".66"/>
<circle cx="205.7" cy="89.1" r=".66"/>
<circle cx="209.1" cy="89.1" r=".66"/>
<circle cx="212.4" cy="89.1" r=".66"/>
<circle cx="221.7" cy="97.5" r=".66"/>
<circle cx="224.1" cy="84" r=".66"/>
<circle cx="226.7" cy="97.3" r=".66"/>
<circle cx="227.5" cy="84" r=".66"/>
<circle cx="230.8" cy="84" r=".66"/>
<circle cx="52" cy="102.3" r=".49"/>
<circle cx="57.8" cy="108.6" r=".49"/>
<circle cx="66.9" cy="108" r=".66"/>
<circle cx="71.9" cy="106.5" r=".49"/>
<circle cx="75.3" cy="107.8" r=".66"/>
<circle cx="78.7" cy="116.9" r=".49"/>
<circle cx="84.4" cy="102" r=".66"/>
<circle cx="85" cy="111.1" r=".49"/>
<circle cx="108.2" cy="117.2" r=".66"/>
<circle cx="111.5" cy="117.2" r=".66"/>
<circle cx="114.8" cy="117.2" r=".66"/>
<circle cx="148.7" cy="117.1" r=".66"/>
<circle cx="152" cy="117.1" r=".66"/>
<circle cx="155.3" cy="117.1" r=".66"/>
<circle cx="176.2" cy="115.9" r=".66"/>
<circle cx="202.4" cy="115.9" r=".66"/>
<circle cx="205.7" cy="115.9" r=".66"/>
<circle cx="209.1" cy="115.9" r=".66"/>
<circle cx="212.4" cy="115.9" r=".66"/>
<circle cx="221.7" cy="100.8" r=".66"/>
<circle cx="226.7" cy="100.7" r=".66"/>
<circle cx="47.9" cy="130.3" r=".49"/>
<circle cx="47.4" cy="155.3" r="1"/>
<circle cx="47.4" cy="152.1" r="1"/>
<circle cx="47.7" cy="140.9" r=".66"/>
</g>
<g fill="none" stroke="#000" stroke-width=".26">
<path d="M64.1 13.2l.7-.2 .5 .5v2.9l-.2 .3-.4 .2-.5-.1-.2-.4v-2.8zM69 10.5l.4-.1h2.8l.5 .2 .1 .5-.2 .4-.4 .2h-2.8l-.6-.5zM69 18.4l.4-.1h2.8l.5 .2 .1 .5-.2 .4-.4 .2h-2.8l-.6-.5zM121.1 12.1l.7-.2 .4 .5v2.2l-.2 .4-.3 .2-.5-.1-.3-.5v-2.1zM128.8 12l.4-.2h2.8l.4 .3 .1 .5-.1 .4-.4 .1h-2.9l-.5-.4zM139.1 12.1l.7-.2 .4 .5v2.2l-.1 .4-.4 .2-.5-.1-.3-.5v-2.1zM61.4 77.9l.3-.1h1.2l.3 .2v.4l-.4 .3h-1.2l-.3-.3zM51.5 84.3l.5-.2 .3 .4v1.2l-.3 .4-.4-.1-.2-.3v-1.1zM56.8 91.1l.3-.2h1.2l.3 .3v.3l-.3 .4h-1.3l-.3-.4zM60.1 81.2l.5-.2 .9 .1 .4 .3v.5l-.5 .4h-1l-.4-.5zM60.3 98.4l.4-.2 1 .1 .3 .3 .1 .5-.5 .4h-1l-.5-.4zM61.6 95.1l.3-.1h1.1l.3 .2 .1 .4-.4 .4-1.2-.1-.3-.3z"/>
<path d="M66.3 90l.6-.2 .4 .4 .1 1.1-.4 .4h-.5l-.4-.4v-.9zM51.7 101.5l.5-.2 .3 .4v1.2l-.3 .4-.4-.1-.3-.3v-1.1zM57 108.3l.3-.2 1.1 .1 .3 .2 .1 .4-.4 .3h-1.2l-.4-.3zM66.4 107.2l.6-.2 .5 .4v1l-.3 .5h-.5l-.4-.3-.1-1zM71.5 105.7l.5-.2 .3 .4v1.2l-.3 .4-.4-.1-.2-.3v-1.1zM74.8 107l.6-.1 .5 .4v1l-.4 .5h-.5l-.3-.4-.1-1zM77.9 116.6l.3-.2h1.1l.3 .3 .1 .3-.4 .4h-1.2l-.4-.4zM83.6 101.6l.4-.2h1l.3 .4v.5l-.5 .4-1-.1-.4-.4zM84.7 110.3l.4-.1 .4 .3v1.2l-.4 .4-.3-.1-.3-.3v-1.1z"/>
</g>
<g fill="none" stroke="#000" stroke-width=".33">
<path d="M55.6 31.8h3.2M57.2 30.1v3.3M154.3 31.8h3.2M155.9 30.1v3.3M55.6 72.6h3.2M57.2 70.9v3.3M154.3 72.6h3.2M155.9 70.9v3.3"/>
<circle cx="57.2" cy="31.8" r="1.64"/>
<circle cx="155.9" cy="31.8" r="1.64"/>
<circle cx="57.2" cy="72.6" r="1.64"/>
<circle cx="155.9" cy="72.6" r="1.64"/>
</g>
<g fill="none" stroke="#000" stroke-width=".4">
<path d="M56.9 8.5h2.9v2.9h-2.9zM166.2 8.5h2.8v2.9h-2.8zM241.2 8.5h2.8v2.9h-2.8zM56.9 113.8h2.9v2.9h-2.9zM166.2 113.8h2.8v2.9h-2.8zM241.2 113.8h2.8v2.9h-2.8z"/>
<circle cx="58.4" cy="10" r="2.01"/>
<circle cx="167.6" cy="10" r="2.01"/>
<circle cx="242.6" cy="10" r="2.01"/>
<circle cx="58.4" cy="115.2" r="2.01"/>
<circle cx="167.6" cy="115.2" r="2.01"/>
<circle cx="242.6" cy="115.2" r="2.01"/>
</g>
<use href="#words"/>
</svg>
